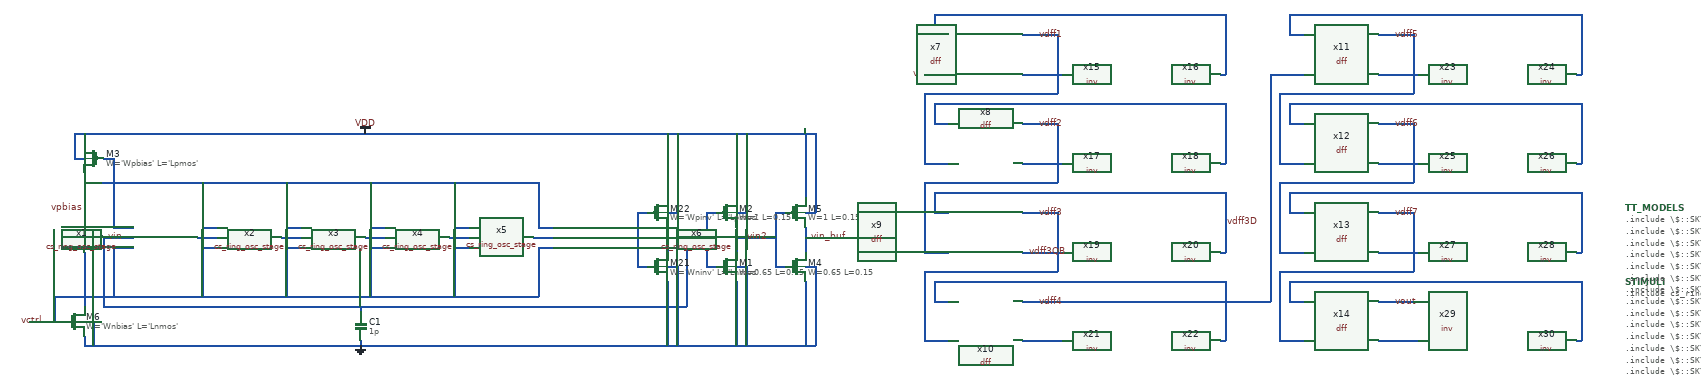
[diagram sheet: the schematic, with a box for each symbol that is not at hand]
v {xschem version=2.9.9 file_version=1.2 }
G {}
K {}
V {}
S {}
E {}
N -1000 -260 -1000 -240 { lab=GND}
N -1000 -290 -980 -290 { lab=GND}
N -980 -290 -980 -240 { lab=GND}
N -1020 -620 -1000 -620 { lab=VDD}
N -1000 -670 -1000 -650 { lab=VDD}
N -1020 -670 -1020 -620 { lab=VDD}
N -1110 -290 -1040 -290 { lab=vctrl}
N -1060 -340 -1060 -290 { lab=vctrl}
N -940 -620 -940 -570 { lab=vpbias}
N -1000 -570 -940 -570 { lab=vpbias}
N -1000 -590 -1000 -490 { lab=vpbias}
N -1000 -430 -1000 -320 { lab=#net1}
N 180 -510 200 -510 { lab=VDD}
N 180 -480 180 -430 { lab=vin}
N 180 -400 200 -400 { lab=GND}
N 120 -510 120 -450 { lab=#net2}
N 120 -510 140 -510 { lab=#net2}
N 120 -450 120 -400 { lab=#net2}
N 120 -400 140 -400 { lab=#net2}
N -960 -620 -940 -620 { lab=vpbias}
N -940 -570 -940 -480 { lab=vpbias}
N -940 -480 -900 -480 { lab=vpbias}
N -1060 -340 -940 -340 { lab=vctrl}
N -940 -440 -940 -340 { lab=vctrl}
N -940 -440 -900 -440 { lab=vctrl}
N -770 -460 -730 -460 { lab=#net3}
N -600 -460 -560 -460 { lab=#net4}
N -430 -460 -390 -460 { lab=#net5}
N -260 -460 -220 -460 { lab=#net6}
N -90 -460 -50 -460 { lab=#net7}
N 80 -460 120 -460 { lab=#net2}
N 180 -670 180 -540 { lab=VDD}
N 200 -670 200 -510 { lab=VDD}
N 180 -370 180 -240 { lab=GND}
N 200 -400 200 -240 { lab=GND}
N -940 -570 -80 -570 { lab=vpbias}
N -80 -570 -80 -480 { lab=vpbias}
N -80 -480 -50 -480 { lab=vpbias}
N -940 -340 -80 -340 { lab=vctrl}
N -80 -440 -80 -340 { lab=vctrl}
N -80 -440 -50 -440 { lab=vctrl}
N -250 -480 -220 -480 { lab=vpbias}
N -250 -570 -250 -480 { lab=vpbias}
N -250 -440 -220 -440 { lab=vctrl}
N -250 -440 -250 -340 { lab=vctrl}
N -420 -480 -390 -480 { lab=vpbias}
N -420 -570 -420 -480 { lab=vpbias}
N -420 -440 -390 -440 { lab=vctrl}
N -420 -440 -420 -340 { lab=vctrl}
N -590 -440 -560 -440 { lab=vctrl}
N -590 -440 -590 -340 { lab=vctrl}
N -590 -480 -560 -480 { lab=vpbias}
N -590 -570 -590 -480 { lab=vpbias}
N -760 -480 -730 -480 { lab=vpbias}
N -760 -570 -760 -480 { lab=vpbias}
N -760 -440 -730 -440 { lab=vctrl}
N -760 -440 -760 -340 { lab=vctrl}
N -960 -460 -900 -460 { lab=vin}
N -960 -460 -960 -320 { lab=vin}
N -960 -320 220 -320 { lab=vin}
N 220 -460 220 -320 { lab=vin}
N 180 -460 220 -460 { lab=vin}
N 700 -790 750 -790 { lab=vin_buf}
N -440 -320 -440 -310 { lab=vin}
N -440 -250 -440 -240 { lab=GND}
N 320 -510 340 -510 { lab=VDD}
N 320 -480 320 -430 { lab=vin2}
N 320 -400 340 -400 { lab=GND}
N 260 -510 260 -450 { lab=vin}
N 260 -510 280 -510 { lab=vin}
N 260 -450 260 -400 { lab=vin}
N 260 -400 280 -400 { lab=vin}
N 320 -670 320 -540 { lab=VDD}
N 340 -670 340 -510 { lab=VDD}
N 320 -370 320 -240 { lab=GND}
N 340 -400 340 -240 { lab=GND}
N 460 -510 480 -510 { lab=VDD}
N 460 -480 460 -430 { lab=vin_buf}
N 460 -400 480 -400 { lab=GND}
N 400 -510 400 -450 { lab=vin2}
N 400 -510 420 -510 { lab=vin2}
N 400 -450 400 -400 { lab=vin2}
N 400 -400 420 -400 { lab=vin2}
N 460 -670 460 -540 { lab=VDD}
N 480 -670 480 -510 { lab=VDD}
N 460 -370 460 -240 { lab=GND}
N 480 -400 480 -240 { lab=GND}
N 460 -460 500 -460 { lab=vin_buf}
N -1020 -670 480 -670 { lab=VDD}
N -1000 -240 480 -240 { lab=GND}
N 320 -460 400 -460 { lab=vin2}
N 220 -460 260 -460 { lab=vin}
N 720 -870 750 -870 { lab=#net8}
N 900 -790 920 -790 { lab=#net9}
N 720 -910 720 -870 { lab=#net8}
N 900 -870 970 -870 { lab=vdff1}
N 700 -610 750 -610 { lab=vdff1}
N 720 -690 750 -690 { lab=#net10}
N 900 -610 920 -610 { lab=#net11}
N 720 -730 720 -690 { lab=#net10}
N 900 -690 970 -690 { lab=vdff2}
N 700 -430 750 -430 { lab=vdff2}
N 720 -510 750 -510 { lab=vdff3D}
N 900 -430 920 -430 { lab=vdff3QB}
N 720 -550 720 -510 { lab=vdff3D}
N 900 -510 970 -510 { lab=vdff3}
N 700 -250 750 -250 { lab=vdff3}
N 720 -330 750 -330 { lab=#net12}
N 900 -250 920 -250 { lab=#net13}
N 720 -370 720 -330 { lab=#net12}
N 900 -330 970 -330 { lab=vdff4}
N 970 -870 970 -750 { lab=vdff1}
N 700 -750 970 -750 { lab=vdff1}
N 700 -750 700 -610 { lab=vdff1}
N 970 -690 970 -570 { lab=vdff2}
N 700 -570 970 -570 { lab=vdff2}
N 700 -570 700 -430 { lab=vdff2}
N 970 -510 970 -390 { lab=vdff3}
N 700 -390 970 -390 { lab=vdff3}
N 700 -390 700 -250 { lab=vdff3}
N 1440 -870 1470 -870 { lab=#net14}
N 1620 -790 1640 -790 { lab=#net15}
N 1440 -910 1440 -870 { lab=#net14}
N 1620 -870 1690 -870 { lab=vdff5}
N 1420 -610 1470 -610 { lab=vdff5}
N 1440 -690 1470 -690 { lab=#net16}
N 1620 -610 1640 -610 { lab=#net17}
N 1440 -730 1440 -690 { lab=#net16}
N 1620 -690 1690 -690 { lab=vdff6}
N 1420 -430 1470 -430 { lab=vdff6}
N 1440 -510 1470 -510 { lab=#net18}
N 1620 -430 1640 -430 { lab=#net19}
N 1440 -550 1440 -510 { lab=#net18}
N 1620 -510 1690 -510 { lab=vdff7}
N 1420 -250 1470 -250 { lab=vdff7}
N 1440 -330 1470 -330 { lab=#net20}
N 1620 -250 1640 -250 { lab=#net21}
N 1440 -370 1440 -330 { lab=#net20}
N 1620 -330 1690 -330 { lab=vout}
N 1690 -870 1690 -750 { lab=vdff5}
N 1420 -750 1690 -750 { lab=vdff5}
N 1420 -750 1420 -610 { lab=vdff5}
N 1690 -690 1690 -570 { lab=vdff6}
N 1420 -570 1690 -570 { lab=vdff6}
N 1420 -570 1420 -430 { lab=vdff6}
N 1690 -510 1690 -390 { lab=vdff7}
N 1420 -390 1690 -390 { lab=vdff7}
N 1420 -390 1420 -250 { lab=vdff7}
N 970 -330 1010 -330 { lab=vdff4}
N 1400 -790 1470 -790 { lab=vdff4}
N 1400 -790 1400 -330 { lab=vdff4}
N 920 -790 980 -790 { lab=#net9}
N 720 -910 1310 -910 { lab=#net8}
N 1310 -910 1310 -790 { lab=#net8}
N 1300 -790 1310 -790 { lab=#net8}
N 920 -610 980 -610 { lab=#net11}
N 720 -730 1310 -730 { lab=#net10}
N 1310 -730 1310 -610 { lab=#net10}
N 1300 -610 1310 -610 { lab=#net10}
N 920 -430 980 -430 { lab=vdff3QB}
N 720 -550 1310 -550 { lab=vdff3D}
N 1310 -550 1310 -430 { lab=vdff3D}
N 1300 -430 1310 -430 { lab=vdff3D}
N 920 -250 980 -250 { lab=#net13}
N 720 -370 1310 -370 { lab=#net12}
N 1310 -370 1310 -250 { lab=#net12}
N 1300 -250 1310 -250 { lab=#net12}
N 1640 -790 1700 -790 { lab=#net15}
N 1440 -910 2030 -910 { lab=#net14}
N 2030 -910 2030 -790 { lab=#net14}
N 2020 -790 2030 -790 { lab=#net14}
N 1640 -610 1700 -610 { lab=#net17}
N 1440 -730 2030 -730 { lab=#net16}
N 2030 -730 2030 -610 { lab=#net16}
N 2020 -610 2030 -610 { lab=#net16}
N 1640 -430 1700 -430 { lab=#net19}
N 1440 -550 2030 -550 { lab=#net18}
N 2030 -550 2030 -430 { lab=#net18}
N 2020 -430 2030 -430 { lab=#net18}
N 1640 -250 1700 -250 { lab=#net21}
N 1440 -370 2030 -370 { lab=#net20}
N 2030 -370 2030 -250 { lab=#net20}
N 2020 -250 2030 -250 { lab=#net20}
N 1010 -330 1400 -330 { lab=vdff4}
C {devices/title.sym} 160 -30 0 0 {name=l1 author="Nikhil Poole"}
C {devices/code.sym} 2120 -370 0 0 {name=STIMULI 
only_toplevel=true
place=end
value=".include cs_ring_osc_div_commands.spice"}
C {devices/code.sym} 2120 -520 0 0 {name=TT_MODELS
only_toplevel=true
format="tcleval( @value )"
value="
.include \\\\$::SKYWATER_MODELS\\\\/cells/nfet_01v8/sky130_fd_pr__nfet_01v8__tt.corner.spice
.include \\\\$::SKYWATER_MODELS\\\\/cells/nfet_01v8_lvt/sky130_fd_pr__nfet_01v8_lvt__tt.corner.spice
.include \\\\$::SKYWATER_MODELS\\\\/cells/pfet_01v8/sky130_fd_pr__pfet_01v8__tt.corner.spice
.include \\\\$::SKYWATER_MODELS\\\\/cells/nfet_03v3_nvt/sky130_fd_pr__nfet_03v3_nvt__tt.corner.spice
.include \\\\$::SKYWATER_MODELS\\\\/cells/nfet_05v0_nvt/sky130_fd_pr__nfet_05v0_nvt__tt.corner.spice
.include \\\\$::SKYWATER_MODELS\\\\/cells/esd_nfet_01v8/sky130_fd_pr__esd_nfet_01v8__tt.corner.spice
.include \\\\$::SKYWATER_MODELS\\\\/cells/pfet_01v8_lvt/sky130_fd_pr__pfet_01v8_lvt__tt.corner.spice
.include \\\\$::SKYWATER_MODELS\\\\/cells/pfet_01v8_hvt/sky130_fd_pr__pfet_01v8_hvt__tt.corner.spice
.include \\\\$::SKYWATER_MODELS\\\\/cells/esd_pfet_g5v0d10v5/sky130_fd_pr__esd_pfet_g5v0d10v5__tt.corner.spice
.include \\\\$::SKYWATER_MODELS\\\\/cells/pfet_g5v0d10v5/sky130_fd_pr__pfet_g5v0d10v5__tt.corner.spice
.include \\\\$::SKYWATER_MODELS\\\\/cells/pfet_g5v0d16v0/sky130_fd_pr__pfet_g5v0d16v0__tt.corner.spice
.include \\\\$::SKYWATER_MODELS\\\\/cells/nfet_g5v0d10v5/sky130_fd_pr__nfet_g5v0d10v5__tt.corner.spice
.include \\\\$::SKYWATER_MODELS\\\\/cells/nfet_g5v0d16v0/sky130_fd_pr__nfet_g5v0d16v0__tt_discrete.corner.spice
.include \\\\$::SKYWATER_MODELS\\\\/cells/esd_nfet_g5v0d10v5/sky130_fd_pr__esd_nfet_g5v0d10v5__tt.corner.spice
.include \\\\$::SKYWATER_MODELS\\\\/models/corners/tt/nonfet.spice
* Standard cells
.include \\\\$::SKYWATER_STDCELLS\\\\/cells/dfxbp/sky130_fd_sc_hd__dfxbp_1.spice
.include \\\\$::SKYWATER_STDCELLS\\\\/cells/dfxbp/sky130_fd_sc_hd__dfxbp_2.spice
* Mismatch parameters
.include \\\\$::SKYWATER_MODELS\\\\/cells/nfet_01v8/sky130_fd_pr__nfet_01v8__mismatch.corner.spice
.include \\\\$::SKYWATER_MODELS\\\\/cells/pfet_01v8/sky130_fd_pr__pfet_01v8__mismatch.corner.spice
.include \\\\$::SKYWATER_MODELS\\\\/cells/nfet_01v8_lvt/sky130_fd_pr__nfet_01v8_lvt__mismatch.corner.spice
.include \\\\$::SKYWATER_MODELS\\\\/cells/pfet_01v8_lvt/sky130_fd_pr__pfet_01v8_lvt__mismatch.corner.spice
.include \\\\$::SKYWATER_MODELS\\\\/cells/pfet_01v8_hvt/sky130_fd_pr__pfet_01v8_hvt__mismatch.corner.spice
.include \\\\$::SKYWATER_MODELS\\\\/cells/nfet_g5v0d10v5/sky130_fd_pr__nfet_g5v0d10v5__mismatch.corner.spice
.include \\\\$::SKYWATER_MODELS\\\\/cells/pfet_g5v0d10v5/sky130_fd_pr__pfet_g5v0d10v5__mismatch.corner.spice
.include \\\\$::SKYWATER_MODELS\\\\/cells/nfet_05v0_nvt/sky130_fd_pr__nfet_05v0_nvt__mismatch.corner.spice
.include \\\\$::SKYWATER_MODELS\\\\/cells/nfet_03v3_nvt/sky130_fd_pr__nfet_03v3_nvt__mismatch.corner.spice
* Resistor\\\\$::SKYWATER_MODELS\\\\/Capacitor
.include \\\\$::SKYWATER_MODELS\\\\/models/r+c/res_typical__cap_typical.spice
.include \\\\$::SKYWATER_MODELS\\\\/models/r+c/res_typical__cap_typical__lin.spice
* Special cells
.include \\\\$::SKYWATER_MODELS\\\\/models/corners/tt/specialized_cells.spice
* All models
.include \\\\$::SKYWATER_MODELS\\\\/models/all.spice
* Corner
.include \\\\$::SKYWATER_MODELS\\\\/models/corners/tt/rf.spice
"}
C {devices/vdd.sym} -430 -670 0 0 {name=l3 lab=VDD}
C {devices/vsource.sym} -1000 -460 0 0 {name=V1 value=0}
C {sky130_fd_pr/nfet_01v8.sym} -1020 -290 0 0 {name=M6
L='Lnmos'
W='Wnbias'
nf=1 
mult='Mnmos'
ad="'int((nf+1)/2) * W/nf * 0.29'" 
pd="'2*int((nf+1)/2) * (W/nf + 0.29)'"
as="'int((nf+2)/2) * W/nf * 0.29'" 
ps="'2*int((nf+2)/2) * (W/nf + 0.29)'"
nrd="'0.29 / W'" nrs="'0.29 / W'"
sa=0 sb=0 sd=0
model=nfet_01v8
spiceprefix=X
}
C {devices/gnd.sym} -440 -240 0 0 {name=l12 lab=GND}
C {devices/lab_wire.sym} -1080 -290 0 0 {name=l2 sig_type=std_logic lab=vctrl}
C {devices/lab_wire.sym} -920 -460 0 0 {name=l5 sig_type=std_logic lab=vin}
C {devices/lab_wire.sym} -1000 -520 0 0 {name=l8 sig_type=std_logic lab=vpbias}
C {sky130_fd_pr/pfet_01v8_hvt.sym} -980 -620 0 1 {name=M3
L='Lpmos'
W='Wpbias'
nf=1
mult='Mpmos'
ad="'int((nf+1)/2) * W/nf * 0.29'" 
pd="'2*int((nf+1)/2) * (W/nf + 0.29)'"
as="'int((nf+2)/2) * W/nf * 0.29'" 
ps="'2*int((nf+2)/2) * (W/nf + 0.29)'"
nrd="'0.29 / W'" nrs="'0.29 / W'"
sa=0 sb=0 sd=0
model=pfet_01v8_hvt
spiceprefix=X
}
C {/home/users/nhpoole/ee272b/ee272b_mixed_signal_mmwave_accelerator/designs/cs_ring_osc_stage.sym} -840 -460 0 0 {name=x1}
C {/home/users/nhpoole/ee272b/ee272b_mixed_signal_mmwave_accelerator/designs/cs_ring_osc_stage.sym} -670 -460 0 0 {name=x2}
C {/home/users/nhpoole/ee272b/ee272b_mixed_signal_mmwave_accelerator/designs/cs_ring_osc_stage.sym} -500 -460 0 0 {name=x3}
C {/home/users/nhpoole/ee272b/ee272b_mixed_signal_mmwave_accelerator/designs/cs_ring_osc_stage.sym} -330 -460 0 0 {name=x4}
C {/home/users/nhpoole/ee272b/ee272b_mixed_signal_mmwave_accelerator/designs/cs_ring_osc_stage.sym} -160 -460 0 0 {name=x5}
C {/home/users/nhpoole/ee272b/ee272b_mixed_signal_mmwave_accelerator/designs/cs_ring_osc_stage.sym} 10 -460 0 0 {name=x6}
C {sky130_fd_pr/nfet_01v8.sym} 160 -400 0 0 {name=M21
L='Lnmos'
W='Wninv'
nf=1
mult='Mnmos'
ad="'int((nf+1)/2) * W/nf * 0.29'" 
pd="'2*int((nf+1)/2) * (W/nf + 0.29)'"
as="'int((nf+2)/2) * W/nf * 0.29'" 
ps="'2*int((nf+2)/2) * (W/nf + 0.29)'"
nrd="'0.29 / W'" nrs="'0.29 / W'"
sa=0 sb=0 sd=0
model=nfet_01v8
spiceprefix=X
}
C {sky130_fd_pr/pfet_01v8_hvt.sym} 160 -510 0 0 {name=M22
L='Lpmos'
W='Wpinv'
nf=1
mult='Mpmos'
ad="'int((nf+1)/2) * W/nf * 0.29'" 
pd="'2*int((nf+1)/2) * (W/nf + 0.29)'"
as="'int((nf+2)/2) * W/nf * 0.29'" 
ps="'2*int((nf+2)/2) * (W/nf + 0.29)'"
nrd="'0.29 / W'" nrs="'0.29 / W'"
sa=0 sb=0 sd=0
model=pfet_01v8_hvt
spiceprefix=X
}
C {devices/lab_wire.sym} 750 -790 0 0 {name=l13 sig_type=std_logic lab=vin_buf}
C {devices/capa.sym} -440 -280 0 0 {name=C1
m=1
value=1p
footprint=1206
device="ceramic capacitor"}
C {sky130_fd_pr/nfet_01v8.sym} 300 -400 0 0 {name=M1
L=0.15
W=0.65
nf=1
mult=1
ad="'int((nf+1)/2) * W/nf * 0.29'" 
pd="'2*int((nf+1)/2) * (W/nf + 0.29)'"
as="'int((nf+2)/2) * W/nf * 0.29'" 
ps="'2*int((nf+2)/2) * (W/nf + 0.29)'"
nrd="'0.29 / W'" nrs="'0.29 / W'"
sa=0 sb=0 sd=0
model=nfet_01v8
spiceprefix=X
}
C {sky130_fd_pr/pfet_01v8_hvt.sym} 300 -510 0 0 {name=M2
L=0.15
W=1
nf=1
mult=1
ad="'int((nf+1)/2) * W/nf * 0.29'" 
pd="'2*int((nf+1)/2) * (W/nf + 0.29)'"
as="'int((nf+2)/2) * W/nf * 0.29'" 
ps="'2*int((nf+2)/2) * (W/nf + 0.29)'"
nrd="'0.29 / W'" nrs="'0.29 / W'"
sa=0 sb=0 sd=0
model=pfet_01v8_hvt
spiceprefix=X
}
C {sky130_fd_pr/nfet_01v8.sym} 440 -400 0 0 {name=M4
L=0.15
W=0.65
nf=1
mult=4
ad="'int((nf+1)/2) * W/nf * 0.29'" 
pd="'2*int((nf+1)/2) * (W/nf + 0.29)'"
as="'int((nf+2)/2) * W/nf * 0.29'" 
ps="'2*int((nf+2)/2) * (W/nf + 0.29)'"
nrd="'0.29 / W'" nrs="'0.29 / W'"
sa=0 sb=0 sd=0
model=nfet_01v8
spiceprefix=X
}
C {sky130_fd_pr/pfet_01v8_hvt.sym} 440 -510 0 0 {name=M5
L=0.15
W=1
nf=1
mult=4
ad="'int((nf+1)/2) * W/nf * 0.29'" 
pd="'2*int((nf+1)/2) * (W/nf + 0.29)'"
as="'int((nf+2)/2) * W/nf * 0.29'" 
ps="'2*int((nf+2)/2) * (W/nf + 0.29)'"
nrd="'0.29 / W'" nrs="'0.29 / W'"
sa=0 sb=0 sd=0
model=pfet_01v8_hvt
spiceprefix=X
}
C {devices/lab_wire.sym} 470 -460 0 1 {name=l4 sig_type=std_logic lab=vin_buf}
C {devices/lab_wire.sym} 340 -460 0 1 {name=l14 sig_type=std_logic lab=vin2}
C {/home/users/nhpoole/ee272b/ee272b_mixed_signal_mmwave_accelerator/designs/dff.sym} 820 -820 0 0 {name=x7 M=1}
C {devices/lab_wire.sym} 930 -870 0 1 {name=l6 sig_type=std_logic lab=vdff1}
C {/home/users/nhpoole/ee272b/ee272b_mixed_signal_mmwave_accelerator/designs/dff.sym} 820 -640 0 0 {name=x8 M=1}
C {devices/lab_wire.sym} 930 -690 0 1 {name=l9 sig_type=std_logic lab=vdff2}
C {/home/users/nhpoole/ee272b/ee272b_mixed_signal_mmwave_accelerator/designs/dff.sym} 820 -460 0 0 {name=x9 M=1}
C {devices/lab_wire.sym} 930 -510 0 1 {name=l11 sig_type=std_logic lab=vdff3}
C {/home/users/nhpoole/ee272b/ee272b_mixed_signal_mmwave_accelerator/designs/dff.sym} 820 -280 0 0 {name=x10 M=1}
C {devices/lab_wire.sym} 930 -330 0 1 {name=l16 sig_type=std_logic lab=vdff4}
C {/home/users/nhpoole/ee272b/ee272b_mixed_signal_mmwave_accelerator/designs/dff.sym} 1540 -820 0 0 {name=x11 M=1}
C {/home/users/nhpoole/ee272b/ee272b_mixed_signal_mmwave_accelerator/designs/dff.sym} 1540 -640 0 0 {name=x12 M=1}
C {/home/users/nhpoole/ee272b/ee272b_mixed_signal_mmwave_accelerator/designs/dff.sym} 1540 -460 0 0 {name=x13 M=1}
C {/home/users/nhpoole/ee272b/ee272b_mixed_signal_mmwave_accelerator/designs/dff.sym} 1540 -280 0 0 {name=x14 M=1}
C {devices/lab_wire.sym} 1650 -330 0 1 {name=l18 sig_type=std_logic lab=vout}
C {devices/lab_wire.sym} 1650 -870 0 1 {name=l7 sig_type=std_logic lab=vdff5}
C {devices/lab_wire.sym} 1650 -690 0 1 {name=l10 sig_type=std_logic lab=vdff6}
C {devices/lab_wire.sym} 1650 -510 0 1 {name=l15 sig_type=std_logic lab=vdff7}
C {/home/users/nhpoole/ee272b/ee272b_mixed_signal_mmwave_accelerator/designs/inv.sym} 1030 -790 0 0 {name=x15 M=1}
C {/home/users/nhpoole/ee272b/ee272b_mixed_signal_mmwave_accelerator/designs/inv.sym} 1190 -790 0 0 {name=x16 M=4}
C {/home/users/nhpoole/ee272b/ee272b_mixed_signal_mmwave_accelerator/designs/inv.sym} 1030 -610 0 0 {name=x17 M=1}
C {/home/users/nhpoole/ee272b/ee272b_mixed_signal_mmwave_accelerator/designs/inv.sym} 1190 -610 0 0 {name=x18 M=4}
C {/home/users/nhpoole/ee272b/ee272b_mixed_signal_mmwave_accelerator/designs/inv.sym} 1030 -430 0 0 {name=x19 M=1}
C {/home/users/nhpoole/ee272b/ee272b_mixed_signal_mmwave_accelerator/designs/inv.sym} 1190 -430 0 0 {name=x20 M=4}
C {/home/users/nhpoole/ee272b/ee272b_mixed_signal_mmwave_accelerator/designs/inv.sym} 1030 -250 0 0 {name=x21 M=1}
C {/home/users/nhpoole/ee272b/ee272b_mixed_signal_mmwave_accelerator/designs/inv.sym} 1190 -250 0 0 {name=x22 M=4}
C {/home/users/nhpoole/ee272b/ee272b_mixed_signal_mmwave_accelerator/designs/inv.sym} 1750 -790 0 0 {name=x23 M=1}
C {/home/users/nhpoole/ee272b/ee272b_mixed_signal_mmwave_accelerator/designs/inv.sym} 1910 -790 0 0 {name=x24 M=4}
C {/home/users/nhpoole/ee272b/ee272b_mixed_signal_mmwave_accelerator/designs/inv.sym} 1750 -610 0 0 {name=x25 M=1}
C {/home/users/nhpoole/ee272b/ee272b_mixed_signal_mmwave_accelerator/designs/inv.sym} 1910 -610 0 0 {name=x26 M=4}
C {/home/users/nhpoole/ee272b/ee272b_mixed_signal_mmwave_accelerator/designs/inv.sym} 1750 -430 0 0 {name=x27 M=1}
C {/home/users/nhpoole/ee272b/ee272b_mixed_signal_mmwave_accelerator/designs/inv.sym} 1910 -430 0 0 {name=x28 M=4}
C {/home/users/nhpoole/ee272b/ee272b_mixed_signal_mmwave_accelerator/designs/inv.sym} 1750 -250 0 0 {name=x29 M=1}
C {/home/users/nhpoole/ee272b/ee272b_mixed_signal_mmwave_accelerator/designs/inv.sym} 1910 -250 0 0 {name=x30 M=4}
C {devices/lab_wire.sym} 910 -430 0 1 {name=l17 sig_type=std_logic lab=vdff3QB}
C {devices/lab_wire.sym} 1310 -490 0 1 {name=l19 sig_type=std_logic lab=vdff3D}
